VERSION 5.7 ;
  NOWIREEXTENSIONATPIN ON ;
  DIVIDERCHAR "/" ;
  BUSBITCHARS "[]" ;
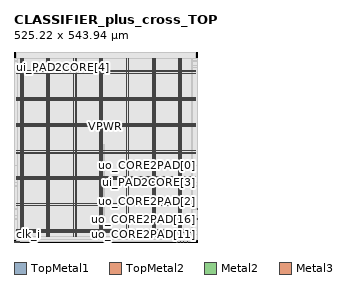
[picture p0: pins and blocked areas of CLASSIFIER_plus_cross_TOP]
MACRO CLASSIFIER_plus_cross_TOP
  CLASS BLOCK ;
  FOREIGN CLASSIFIER_plus_cross_TOP ;
  ORIGIN 0.000 0.000 ;
  SIZE 525.220 BY 543.940 ;
  PIN VGND
    DIRECTION INOUT ;
    USE GROUND ;
    PORT
      LAYER TopMetal1 ;
        RECT 24.460 14.490 26.660 525.640 ;
    END
    PORT
      LAYER TopMetal1 ;
        RECT 100.060 14.490 102.260 525.640 ;
    END
    PORT
      LAYER TopMetal1 ;
        RECT 175.660 14.490 177.860 525.640 ;
    END
    PORT
      LAYER TopMetal1 ;
        RECT 251.260 14.490 253.460 525.640 ;
    END
    PORT
      LAYER TopMetal1 ;
        RECT 326.860 14.490 329.060 525.640 ;
    END
    PORT
      LAYER TopMetal1 ;
        RECT 402.460 14.490 404.660 525.640 ;
    END
    PORT
      LAYER TopMetal1 ;
        RECT 478.060 14.490 480.260 525.640 ;
    END
    PORT
      LAYER TopMetal2 ;
        RECT 5.760 33.820 519.360 36.020 ;
    END
    PORT
      LAYER TopMetal2 ;
        RECT 5.760 109.420 519.360 111.620 ;
    END
    PORT
      LAYER TopMetal2 ;
        RECT 5.760 185.020 519.360 187.220 ;
    END
    PORT
      LAYER TopMetal2 ;
        RECT 5.760 260.620 519.360 262.820 ;
    END
    PORT
      LAYER TopMetal2 ;
        RECT 5.760 336.220 519.360 338.420 ;
    END
    PORT
      LAYER TopMetal2 ;
        RECT 5.760 411.820 519.360 414.020 ;
    END
    PORT
      LAYER TopMetal2 ;
        RECT 5.760 487.420 519.360 489.620 ;
    END
  END VGND
  PIN VPWR
    DIRECTION INOUT ;
    USE POWER ;
    PORT
      LAYER TopMetal1 ;
        RECT 18.260 14.900 20.460 526.050 ;
    END
    PORT
      LAYER TopMetal1 ;
        RECT 93.860 14.900 96.060 526.050 ;
    END
    PORT
      LAYER TopMetal1 ;
        RECT 169.460 14.900 171.660 526.050 ;
    END
    PORT
      LAYER TopMetal1 ;
        RECT 245.060 14.900 247.260 526.050 ;
    END
    PORT
      LAYER TopMetal1 ;
        RECT 320.660 14.900 322.860 526.050 ;
    END
    PORT
      LAYER TopMetal1 ;
        RECT 396.260 14.900 398.460 526.050 ;
    END
    PORT
      LAYER TopMetal1 ;
        RECT 471.860 14.900 474.060 526.050 ;
    END
    PORT
      LAYER TopMetal2 ;
        RECT 5.760 27.620 519.360 29.820 ;
    END
    PORT
      LAYER TopMetal2 ;
        RECT 5.760 103.220 519.360 105.420 ;
    END
    PORT
      LAYER TopMetal2 ;
        RECT 5.760 178.820 519.360 181.020 ;
    END
    PORT
      LAYER TopMetal2 ;
        RECT 5.760 254.420 519.360 256.620 ;
    END
    PORT
      LAYER TopMetal2 ;
        RECT 5.760 330.020 519.360 332.220 ;
    END
    PORT
      LAYER TopMetal2 ;
        RECT 5.760 405.620 519.360 407.820 ;
    END
    PORT
      LAYER TopMetal2 ;
        RECT 5.760 481.220 519.360 483.420 ;
    END
  END VPWR
  PIN clk_i
    DIRECTION INPUT ;
    USE SIGNAL ;
    PORT
      LAYER Metal2 ;
        RECT 2.200 0.000 2.600 0.400 ;
    END
  END clk_i
  PIN rst_ni
    DIRECTION INPUT ;
    USE SIGNAL ;
    PORT
      LAYER Metal2 ;
        RECT 3.160 0.000 3.560 0.400 ;
    END
  END rst_ni
  PIN ui_PAD2CORE[0]
    DIRECTION INPUT ;
    USE SIGNAL ;
    ANTENNAGATEAREA 0.180700 ;
    PORT
      LAYER Metal3 ;
        RECT 524.820 21.220 525.220 21.620 ;
    END
  END ui_PAD2CORE[0]
  PIN ui_PAD2CORE[10]
    DIRECTION INPUT ;
    USE SIGNAL ;
    PORT
      LAYER Metal2 ;
        RECT 4.120 0.000 4.520 0.400 ;
    END
  END ui_PAD2CORE[10]
  PIN ui_PAD2CORE[11]
    DIRECTION INPUT ;
    USE SIGNAL ;
    PORT
      LAYER Metal2 ;
        RECT 5.080 0.000 5.480 0.400 ;
    END
  END ui_PAD2CORE[11]
  PIN ui_PAD2CORE[12]
    DIRECTION INPUT ;
    USE SIGNAL ;
    PORT
      LAYER Metal2 ;
        RECT 6.040 0.000 6.440 0.400 ;
    END
  END ui_PAD2CORE[12]
  PIN ui_PAD2CORE[13]
    DIRECTION INPUT ;
    USE SIGNAL ;
    PORT
      LAYER Metal2 ;
        RECT 7.000 0.000 7.400 0.400 ;
    END
  END ui_PAD2CORE[13]
  PIN ui_PAD2CORE[14]
    DIRECTION INPUT ;
    USE SIGNAL ;
    PORT
      LAYER Metal2 ;
        RECT 7.960 0.000 8.360 0.400 ;
    END
  END ui_PAD2CORE[14]
  PIN ui_PAD2CORE[15]
    DIRECTION INPUT ;
    USE SIGNAL ;
    PORT
      LAYER Metal2 ;
        RECT 8.920 0.000 9.320 0.400 ;
    END
  END ui_PAD2CORE[15]
  PIN ui_PAD2CORE[16]
    DIRECTION INPUT ;
    USE SIGNAL ;
    PORT
      LAYER Metal2 ;
        RECT 9.880 0.000 10.280 0.400 ;
    END
  END ui_PAD2CORE[16]
  PIN ui_PAD2CORE[1]
    DIRECTION INPUT ;
    USE SIGNAL ;
    ANTENNAGATEAREA 0.180700 ;
    PORT
      LAYER Metal3 ;
        RECT 0.000 500.020 0.400 500.420 ;
    END
  END ui_PAD2CORE[1]
  PIN ui_PAD2CORE[2]
    DIRECTION INPUT ;
    USE SIGNAL ;
    ANTENNAGATEAREA 0.180700 ;
    PORT
      LAYER Metal2 ;
        RECT 330.520 543.540 330.920 543.940 ;
    END
  END ui_PAD2CORE[2]
  PIN ui_PAD2CORE[3]
    DIRECTION INPUT ;
    USE SIGNAL ;
    ANTENNAGATEAREA 0.180700 ;
    PORT
      LAYER Metal3 ;
        RECT 524.820 169.900 525.220 170.300 ;
    END
  END ui_PAD2CORE[3]
  PIN ui_PAD2CORE[4]
    DIRECTION INPUT ;
    USE SIGNAL ;
    ANTENNAGATEAREA 0.180700 ;
    PORT
      LAYER Metal3 ;
        RECT 0.000 499.180 0.400 499.580 ;
    END
  END ui_PAD2CORE[4]
  PIN ui_PAD2CORE[5]
    DIRECTION INPUT ;
    USE SIGNAL ;
    PORT
      LAYER Metal2 ;
        RECT 10.840 0.000 11.240 0.400 ;
    END
  END ui_PAD2CORE[5]
  PIN ui_PAD2CORE[6]
    DIRECTION INPUT ;
    USE SIGNAL ;
    PORT
      LAYER Metal2 ;
        RECT 11.800 0.000 12.200 0.400 ;
    END
  END ui_PAD2CORE[6]
  PIN ui_PAD2CORE[7]
    DIRECTION INPUT ;
    USE SIGNAL ;
    PORT
      LAYER Metal2 ;
        RECT 12.760 0.000 13.160 0.400 ;
    END
  END ui_PAD2CORE[7]
  PIN ui_PAD2CORE[8]
    DIRECTION INPUT ;
    USE SIGNAL ;
    PORT
      LAYER Metal2 ;
        RECT 13.720 0.000 14.120 0.400 ;
    END
  END ui_PAD2CORE[8]
  PIN ui_PAD2CORE[9]
    DIRECTION INPUT ;
    USE SIGNAL ;
    PORT
      LAYER Metal2 ;
        RECT 14.680 0.000 15.080 0.400 ;
    END
  END ui_PAD2CORE[9]
  PIN uo_CORE2PAD[0]
    DIRECTION OUTPUT ;
    USE SIGNAL ;
    ANTENNADIFFAREA 0.708600 ;
    PORT
      LAYER Metal3 ;
        RECT 524.820 218.620 525.220 219.020 ;
    END
  END uo_CORE2PAD[0]
  PIN uo_CORE2PAD[10]
    DIRECTION OUTPUT ;
    USE SIGNAL ;
    ANTENNADIFFAREA 0.299200 ;
    PORT
      LAYER Metal3 ;
        RECT 524.820 505.900 525.220 506.300 ;
    END
  END uo_CORE2PAD[10]
  PIN uo_CORE2PAD[11]
    DIRECTION OUTPUT ;
    USE SIGNAL ;
    ANTENNADIFFAREA 0.299200 ;
    PORT
      LAYER Metal2 ;
        RECT 486.040 0.000 486.440 0.400 ;
    END
  END uo_CORE2PAD[11]
  PIN uo_CORE2PAD[12]
    DIRECTION OUTPUT ;
    USE SIGNAL ;
    ANTENNADIFFAREA 0.299200 ;
    PORT
      LAYER Metal2 ;
        RECT 477.400 0.000 477.800 0.400 ;
    END
  END uo_CORE2PAD[12]
  PIN uo_CORE2PAD[13]
    DIRECTION OUTPUT ;
    USE SIGNAL ;
    ANTENNADIFFAREA 0.299200 ;
    PORT
      LAYER Metal2 ;
        RECT 464.920 0.000 465.320 0.400 ;
    END
  END uo_CORE2PAD[13]
  PIN uo_CORE2PAD[14]
    DIRECTION OUTPUT ;
    USE SIGNAL ;
    ANTENNADIFFAREA 0.299200 ;
    PORT
      LAYER Metal2 ;
        RECT 466.840 0.000 467.240 0.400 ;
    END
  END uo_CORE2PAD[14]
  PIN uo_CORE2PAD[15]
    DIRECTION OUTPUT ;
    USE SIGNAL ;
    ANTENNADIFFAREA 0.299200 ;
    PORT
      LAYER Metal3 ;
        RECT 0.000 516.820 0.400 517.220 ;
    END
  END uo_CORE2PAD[15]
  PIN uo_CORE2PAD[16]
    DIRECTION OUTPUT ;
    USE SIGNAL ;
    ANTENNADIFFAREA 0.299200 ;
    PORT
      LAYER Metal3 ;
        RECT 524.820 64.900 525.220 65.300 ;
    END
  END uo_CORE2PAD[16]
  PIN uo_CORE2PAD[1]
    DIRECTION OUTPUT ;
    USE SIGNAL ;
    ANTENNADIFFAREA 0.708600 ;
    PORT
      LAYER Metal3 ;
        RECT 524.820 159.820 525.220 160.220 ;
    END
  END uo_CORE2PAD[1]
  PIN uo_CORE2PAD[2]
    DIRECTION OUTPUT ;
    USE SIGNAL ;
    ANTENNADIFFAREA 0.708600 ;
    PORT
      LAYER Metal3 ;
        RECT 524.820 94.300 525.220 94.700 ;
    END
  END uo_CORE2PAD[2]
  PIN uo_CORE2PAD[3]
    DIRECTION OUTPUT ;
    USE SIGNAL ;
    ANTENNADIFFAREA 0.299200 ;
    PORT
      LAYER Metal2 ;
        RECT 445.720 543.540 446.120 543.940 ;
    END
  END uo_CORE2PAD[3]
  PIN uo_CORE2PAD[4]
    DIRECTION OUTPUT ;
    USE SIGNAL ;
    ANTENNADIFFAREA 0.299200 ;
    PORT
      LAYER Metal2 ;
        RECT 465.880 0.000 466.280 0.400 ;
    END
  END uo_CORE2PAD[4]
  PIN uo_CORE2PAD[5]
    DIRECTION OUTPUT ;
    USE SIGNAL ;
    ANTENNADIFFAREA 0.299200 ;
    PORT
      LAYER Metal3 ;
        RECT 524.820 32.980 525.220 33.380 ;
    END
  END uo_CORE2PAD[5]
  PIN uo_CORE2PAD[6]
    DIRECTION OUTPUT ;
    USE SIGNAL ;
    ANTENNADIFFAREA 0.299200 ;
    PORT
      LAYER Metal2 ;
        RECT 496.600 0.000 497.000 0.400 ;
    END
  END uo_CORE2PAD[6]
  PIN uo_CORE2PAD[7]
    DIRECTION OUTPUT ;
    USE SIGNAL ;
    ANTENNADIFFAREA 0.299200 ;
    PORT
      LAYER Metal3 ;
        RECT 524.820 65.740 525.220 66.140 ;
    END
  END uo_CORE2PAD[7]
  PIN uo_CORE2PAD[8]
    DIRECTION OUTPUT ;
    USE SIGNAL ;
    ANTENNADIFFAREA 0.299200 ;
    PORT
      LAYER Metal3 ;
        RECT 524.820 74.980 525.220 75.380 ;
    END
  END uo_CORE2PAD[8]
  PIN uo_CORE2PAD[9]
    DIRECTION OUTPUT ;
    USE SIGNAL ;
    ANTENNADIFFAREA 0.299200 ;
    PORT
      LAYER Metal3 ;
        RECT 0.000 517.660 0.400 518.060 ;
    END
  END uo_CORE2PAD[9]
  OBS
      LAYER GatPoly ;
        RECT 5.760 14.970 519.360 525.570 ;
      LAYER Metal1 ;
        RECT 5.760 14.900 519.360 525.640 ;
      LAYER Metal2 ;
        RECT 6.135 543.330 330.310 543.540 ;
        RECT 331.130 543.330 445.510 543.540 ;
        RECT 446.330 543.330 519.460 543.540 ;
        RECT 6.135 0.610 519.460 543.330 ;
        RECT 6.650 0.100 6.790 0.610 ;
        RECT 7.610 0.100 7.750 0.610 ;
        RECT 8.570 0.100 8.710 0.610 ;
        RECT 9.530 0.100 9.670 0.610 ;
        RECT 10.490 0.100 10.630 0.610 ;
        RECT 11.450 0.100 11.590 0.610 ;
        RECT 12.410 0.100 12.550 0.610 ;
        RECT 13.370 0.100 13.510 0.610 ;
        RECT 14.330 0.100 14.470 0.610 ;
        RECT 15.290 0.100 464.710 0.610 ;
        RECT 465.530 0.100 465.670 0.610 ;
        RECT 466.490 0.100 466.630 0.610 ;
        RECT 467.450 0.100 477.190 0.610 ;
        RECT 478.010 0.100 485.830 0.610 ;
        RECT 486.650 0.100 496.390 0.610 ;
        RECT 497.210 0.100 519.460 0.610 ;
      LAYER Metal3 ;
        RECT 0.400 518.270 524.820 525.520 ;
        RECT 0.610 517.450 524.820 518.270 ;
        RECT 0.400 517.430 524.820 517.450 ;
        RECT 0.610 516.610 524.820 517.430 ;
        RECT 0.400 506.510 524.820 516.610 ;
        RECT 0.400 505.690 524.610 506.510 ;
        RECT 0.400 500.630 524.820 505.690 ;
        RECT 0.610 499.810 524.820 500.630 ;
        RECT 0.400 499.790 524.820 499.810 ;
        RECT 0.610 498.970 524.820 499.790 ;
        RECT 0.400 219.230 524.820 498.970 ;
        RECT 0.400 218.410 524.610 219.230 ;
        RECT 0.400 170.510 524.820 218.410 ;
        RECT 0.400 169.690 524.610 170.510 ;
        RECT 0.400 160.430 524.820 169.690 ;
        RECT 0.400 159.610 524.610 160.430 ;
        RECT 0.400 94.910 524.820 159.610 ;
        RECT 0.400 94.090 524.610 94.910 ;
        RECT 0.400 75.590 524.820 94.090 ;
        RECT 0.400 74.770 524.610 75.590 ;
        RECT 0.400 66.350 524.820 74.770 ;
        RECT 0.400 65.530 524.610 66.350 ;
        RECT 0.400 65.510 524.820 65.530 ;
        RECT 0.400 64.690 524.610 65.510 ;
        RECT 0.400 33.590 524.820 64.690 ;
        RECT 0.400 32.770 524.610 33.590 ;
        RECT 0.400 21.830 524.820 32.770 ;
        RECT 0.400 21.010 524.610 21.830 ;
        RECT 0.400 7.880 524.820 21.010 ;
      LAYER Metal4 ;
        RECT 9.495 14.975 510.820 525.565 ;
      LAYER Metal5 ;
        RECT 9.455 14.810 509.425 525.730 ;
      LAYER TopMetal1 ;
        RECT 256.180 47.060 257.820 278.440 ;
  END
END CLASSIFIER_plus_cross_TOP
END LIBRARY

